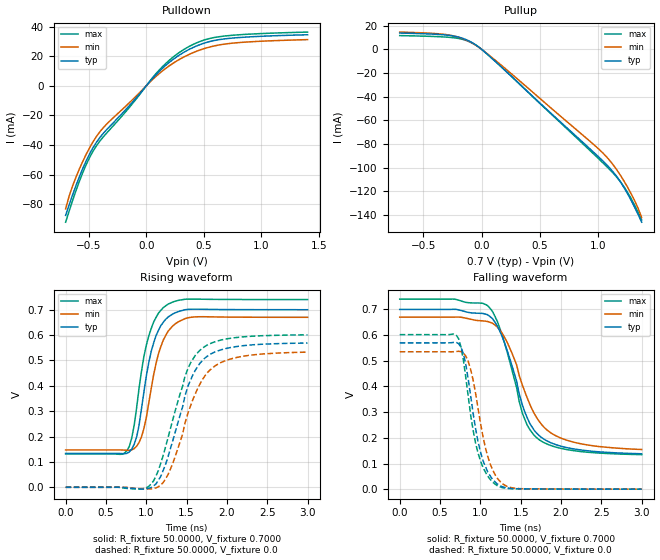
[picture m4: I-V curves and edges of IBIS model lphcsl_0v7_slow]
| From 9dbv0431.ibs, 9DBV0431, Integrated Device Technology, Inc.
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[Model]   lphcsl_0v7_slow
Model_type Output
Polarity   Non-Inverting
Enable   Active-High
Vmeas =  0.4000V
Cref =   2.0000pF
Rref =   0.0
Vref =   0.4000V
C_comp   1.1000pF   1.0000pF   1.2000pF
[Temperature Range]   25.0000   75.0000   0.0
[Voltage Range]   0.7000V   0.6700V   0.7400V
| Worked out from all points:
|   slope of the pulldown table from 0 to 0.105 V, typ, clamps not added: 11.5 ohm
|   slope of the pullup table from 0 to 0.105 V, typ, clamps not added: 11.5 ohm
|   rising waveform, R_fixture 50.0000, V_fixture 0.7000: 20-80 % time 198ps typ, 209ps min, 199ps max; typ from 0.134 V to 0.7 V
|   rising waveform, R_fixture 50.0000, V_fixture 0.0: 20-80 % time 334ps typ, 357ps min, 330ps max; typ from 0 V to 0.568 V
|   falling waveform, R_fixture 50.0000, V_fixture 0.7000: 20-80 % time 346ps typ, 405ps min, 323ps max; typ from 0.7 V to 0.138 V
|   falling waveform, R_fixture 50.0000, V_fixture 0.0: 20-80 % time 195ps typ, 205ps min, 192ps max; typ from 0.57 V to 0 V
[Pulldown]
|Voltage   I(typ)   I(min)   I(max)
-700mV    -87.46mA   -83.06mA   -92.05mA
-640mV    -73.75mA   -67.7mA    -77.54mA
-580mV    -61.27mA   -56.03mA   -64.32mA
-490mV    -45.66mA   -41.53mA   -48.1mA
-430mV    -37.82mA   -33.91mA   -40.19mA
-340mV    -29.28mA   -25.55mA   -31.55mA
50mV      4.609mA    3.896mA    5.041mA
230mV     17.65mA    15.08mA    19.19mA
410mV     26mA       22.5mA     28.05mA
590mV     30.57mA    26.92mA    32.6mA
860mV     32.86mA    29.49mA    34.71mA
1.4V      34.46mA    31.17mA    36.26mA
[Pullup]
|Voltage   I(typ)   I(min)   I(max)
-700mV    13.69mA    14.51mA    11.54mA
-370mV    12.52mA    13.09mA    10.63mA
-220mV    10.82mA    10.77mA    9.497mA
-100mV    6.649mA    6.27mA     6.197mA
-10mV     821.9uA    747.4uA    796.9uA
290mV     -26.07mA   -23.65mA   -26.13mA
1.04V     -94.6mA    -87.89mA   -96.18mA
1.13V     -104.2mA   -98.2mA    -105.1mA
1.22V     -117.1mA   -111.6mA   -116.4mA
1.31V     -133.6mA   -128mA     -131.9mA
1.34V     -139.7mA   -134.5mA   -137.9mA
1.37V     -146.2mA   -142.3mA   -144.3mA
[Ramp]
| variable   typ   min   max
dV/dt_r  0.3411/0.3543n   0.3196/0.3772n   0.3605/0.3504n
dV/dt_f  0.3373/0.3660n   0.3093/0.4253n   0.3633/0.3432n
R_load = 50.0000
[Rising Waveform]
R_fixture= 50.0000
V_fixture= 0.7000
V_fixture_min= 0.6700
V_fixture_max= 0.7400
|time   V(typ)   V(min)   V(max)
0s        133.6mV    147.2mV    131.3mV
760ps     133.9mV    146mV      144.2mV
820ps     150.6mV    147.5mV    194.5mV
880ps     197.9mV    161.8mV    312.5mV
970ps     374.1mV    231mV      514.7mV
1.03ns    489.9mV    330.7mV    595.4mV
1.15ns    617.7mV    524.8mV    685.8mV
1.27ns    670.9mV    614.9mV    721.8mV
1.58ns    702.2mV    671.2mV    741.9mV
3ns       700mV      670.1mV    740mV
[Rising Waveform]
R_fixture= 50.0000
V_fixture= 0.0
V_fixture_min= 0.0
V_fixture_max= 0.0
|time   V(typ)   V(min)   V(max)
0s        0V         0V         0V
910ps     -5.931mV   -4.903mV   -7.385mV
1.06ns    -939.7uV   -6.11mV    13.08mV
1.18ns    43.05mV    9.678mV    95.3mV
1.27ns    120.7mV    50.09mV    195.7mV
1.45ns    316.4mV    209mV      397.7mV
1.52ns    400.9mV    295.4mV    470.7mV
1.73ns    510.3mV    440.4mV    555.9mV
2.12ns    554.9mV    511.7mV    590.5mV
3ns       568.5mV    532.7mV    600.9mV
[Falling Waveform]
R_fixture= 50.0000
V_fixture= 0.7000
V_fixture_min= 0.6700
V_fixture_max= 0.7400
|time   V(typ)   V(min)   V(max)
0s        700mV      670mV      740mV
1.09ns    679.3mV    652.8mV    714.8mV
1.27ns    594.8mV    607.6mV    600.4mV
1.42ns    451.7mV    507.5mV    430.4mV
1.52ns    328.7mV    406mV      297mV
1.61ns    257.7mV    333.4mV    233.8mV
1.73ns    208.3mV    263.8mV    192.2mV
1.88ns    180mV      217.9mV    169.5mV
2.15ns    157.2mV    183.7mV    150.4mV
3ns       137.9mV    154.5mV    134.5mV
[Falling Waveform]
R_fixture= 50.0000
V_fixture= 0.0
V_fixture_min= 0.0
V_fixture_max= 0.0
|time   V(typ)   V(min)   V(max)
0s        569.8mV    535.1mV    601.7mV
700ps     572mV      536.1mV    600.6mV
760ps     552.1mV    535.3mV    553.9mV
820ps     484.8mV    517.6mV    433.8mV
880ps     362.9mV    465.4mV    287.9mV
970ps     186.5mV    317.4mV    141.9mV
1.09ns    67.97mV    129.3mV    51.29mV
1.21ns    20.24mV    42.46mV    13.66mV
1.48ns    1.52mV     2.392mV    1.278mV
3ns       112uV      169.4uV    88.78uV
